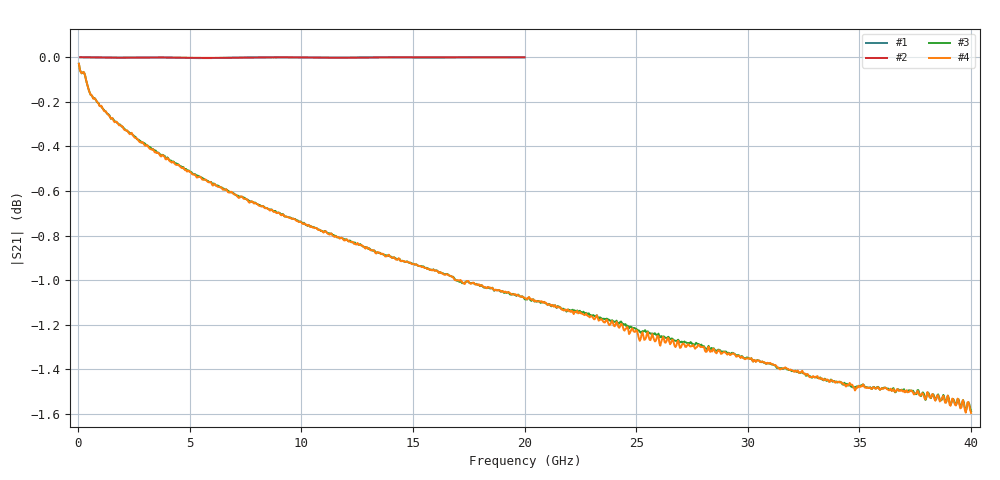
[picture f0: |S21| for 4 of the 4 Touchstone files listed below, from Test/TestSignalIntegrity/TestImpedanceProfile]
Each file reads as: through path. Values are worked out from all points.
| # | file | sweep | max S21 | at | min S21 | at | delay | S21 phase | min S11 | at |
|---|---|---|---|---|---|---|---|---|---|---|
| 1 | cableLeftSide.s2p | 100 MHz to 20 GHz | 0.00 dB | 18.1 GHz | 0.0 dB | 5.5 GHz | 150 ps | 175 deg at 10.1 GHz | -61.7 dB | 18.1 GHz |
| 2 | cableRightSide.s2p | 100 MHz to 20 GHz | 0.00 dB | 20 GHz | 0.0 dB | 5.8 GHz | 150 ps | 175 deg at 10.1 GHz | -60.7 dB | 20 GHz |
| 3 | TestImpedanceProfile_testPeelCableforRLGC_deembedded_causal.s2p | 40 MHz to 40 GHz | -0.03 dB | 40 MHz | -1.6 dB | 40 GHz | - | -100 deg at 20.04 GHz | -72.0 dB | 3.56 GHz |
| 4 | TestImpedanceProfile_testPeelCableforRLGC_gated.s2p | 40 MHz to 40 GHz | -0.03 dB | 40 MHz | -1.6 dB | 40 GHz | - | -140 deg at 20.04 GHz | -59.1 dB | 10.2 GHz |
